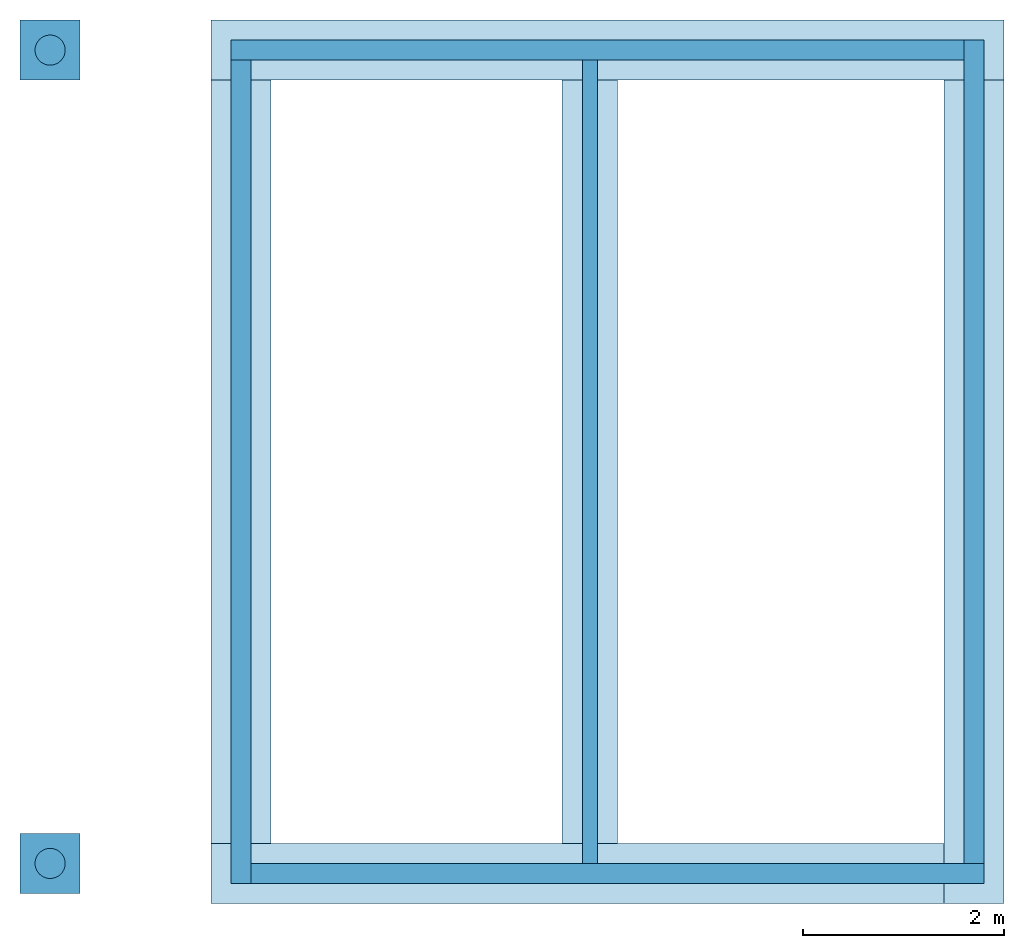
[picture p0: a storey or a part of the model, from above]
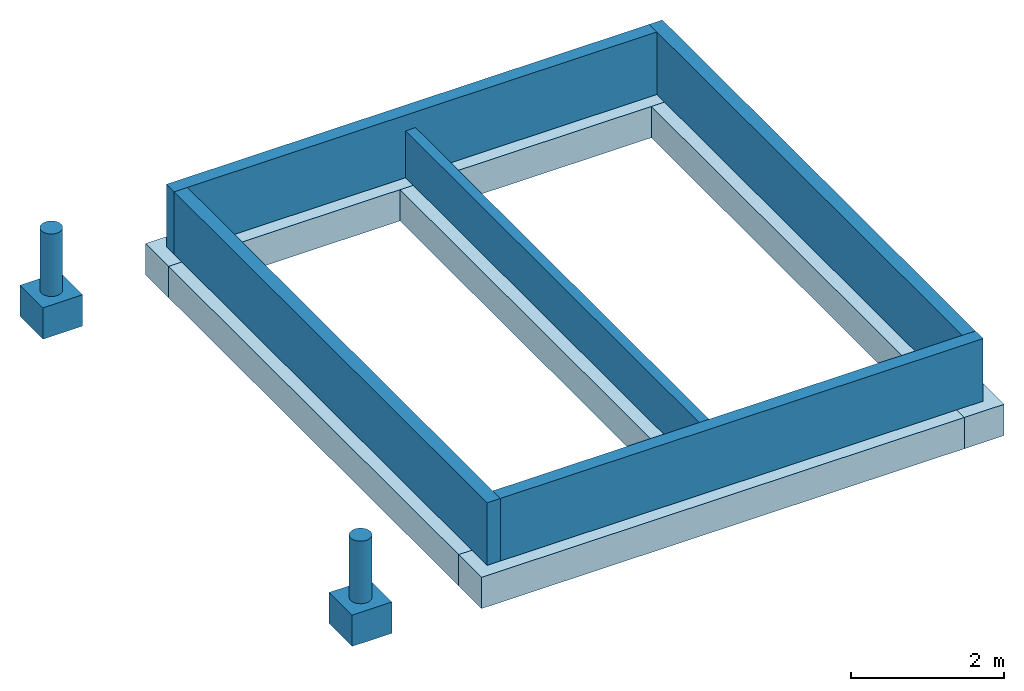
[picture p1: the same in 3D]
Properties of the parts of a building model (IFC2X3)

# File
Description: ViewDefinition [CoordinationView, QuantityTakeOffAddOnView]
File name: Numéro du projet
Time: 2016-11-08T15:51:28
Written by: The EXPRESS Data Manager Version 5.02.0100.07 : 28 Aug 2013
Made in: 20150220_1215(x64) - Exporter 16.0.428.0 - Default UI
Comment: STEP Physical File produced by: The EXPRESS Data Manager Version 5.02.0100.07 : 28 Aug 2013 * Module: EDMstepFileFactory/EDMstandAlone * Creation date: Tue Nov 08 15:51:28 2016 * Host: FC214POSTEPROF * Database: C:\Users\poutead\AppData\Local\Temp\{FD1324F0-440A-46DE-A54C-80044E7AAA6C}\ifc * Database version: 5507 * Database creation date: Tue Nov 08 15:51:26 2016 * Schema: IFC2X3 * Model: DataRepository.ifc * Model creation date: Tue Nov 08 15:51:26 2016 * Header model: DataRepository.ifc_HeaderModel * Header model creation date: Tue Nov 08 15:51:26 2016 * EDMuser: sdai-user * EDMgroup: sdai-group * License ID and type: 5605 : Permanent license. Expiry date: * EDMstepFileFactory options: 020000

# IfcProject, Numéro du projet
LongName: Nom du projet; Phase: Etat du projet

# IfcSite, Default
RefLatitude: 48, 51, 23, 999633; RefLongitude: 2, 21, 3, 553905; RefElevation: 0 m
Autre - Adresse du projet: Entrer l'adresse ici; Catégorie: Informations sur le projet; Date de fin du projet: Date de fin; Etat du projet: Etat du projet; Nom du client: Propriétaire; Nom du projet: Nom du projet; Numéro de projet: Numéro du projet

# IfcBuilding
Pset_BuildingCommon - NumberOfStoreys: 4
Autre - Catégorie: Informations sur le projet; Adresse du projet: Entrer l'adresse ici; Date de fin du projet: Date de fin; Etat du projet: Etat du projet; Nom du client: Propriétaire; Nom du projet: Nom du projet; Numéro de projet: Numéro du projet

# IfcBuildingStorey (4)
Autre - Catégorie: Niveaux; Famille: Niveau: Ligne du Niveau; Famille et type: Niveau: Ligne du Niveau; ID du type: Niveau: Ligne du Niveau; Type: Niveau: Ligne du Niveau; Nom de la famille: Niveau
Cotes - Hauteur de calcul: 0 m
Données d'identification - Structure: no; Etage de bâtiment: yes; Nom du type: Ligne du Niveau
Contraintes - Base de l'élévation: Point de base du projet
Graphismes - Couleur: 12632256; Epaisseur des lignes: 1; Motif des lignes: Tiret point; Symbole: Marqueur de niveau - Point triangulaire: Marqueur de niveau - Point triangulaire; Valeur par défaut du symbole à l'extrémité 1: no; Valeur par défaut du symbole à l'extrémité 2: yes
Name | LongName = Nom | Elevation (m) | Elévation (m)
0_Fondations | 0_Fondations | -1 | -1
Niveau 0 | Niveau 0 | -1.94916e-14 | 0
Niveau 1 | Niveau 1 | 3 | 3
Niveau 2 | Niveau 2 | 6 | 6

# IfcBeam: Poutre rectangulaire - Béton:300 x 600 mm:240493 (3)
In: Niveau 1
Material: Béton - Béton coulé sur place
Pset_BeamCommon - IsExternal: no; LoadBearing: yes; Slope: 0 deg; Reference: 300 x 600 mm
Autre - Catégorie: Ossature; Famille: Poutre rectangulaire - Béton: 300 x 600 mm; Famille et type: Poutre rectangulaire - Béton: 300 x 600 mm; ID du type: Poutre rectangulaire - Béton: 300 x 600 mm; Type: Poutre rectangulaire - Béton: 300 x 600 mm; Nom de la famille: Poutre rectangulaire - Béton
Contraintes - Décalage du niveau d'arrivée: 0 m; Décalage du niveau de départ: 0 m; Elévation du niveau de référence: 3 m; Niveau de référence: Niveau: Niveau 1; Orientation: Normale; Plan de construction: Niveau : Niveau 1; Rotation de la section: 0 deg
Cotes - Elévation à la base: 2.6 m; Elévation en haut: 3 m; b: 0.3 m; h: 0.4 m
Matériaux et finitions - Matériau structurel: Béton - Béton coulé sur place
Phase de construction - Phase de création: Nouvelle construction
Position géométrique - Etat de la jonction: Deux jonctions activées; Justification Y: Origine; Justification YZ: Uniforme; Justification Z: Haut; Valeur de décalage Y: 0 m; Valeur de décalage Z: 0 m
Structure - Enrobage d'armature - Autres faces: Paramètres de l'enrobage d'armature: Enrobage d'armature 1; Enrobage d'armature - Face inférieure: Paramètres de l'enrobage d'armature: Enrobage d'armature 1; Enrobage d'armature - Face supérieure: Paramètres de l'enrobage d'armature: Enrobage d'armature 1; Activer le modèle analytique: yes; Forme de coupe: 0
Données d'identification - Nom du type: 300 x 600 mm
Name (Poutre rectangulaire - Béton:300 x 600 mm:...) | GrossVolume (m3) | Span (m) = Longueur (m) | Surface (m2) | Volume (m3) | Longueur de coupe (m) | Utilisation structurelle
240555 | 0.788465 | 1.94 | 1.56189 | 0.240324 | 2.1027 | Autre
240597 | 0.764843 | 1.94 | 1.54389 | 0.233124 | 2.1027 | Autre
240628 | 3.18898 | 8.1 | 5.79 | 0.972 | 8.1 | Longeron | Structure - Type d'attachement de début: Elévation d'arrivée; Type d'attachement de fin: Elévation d'arrivée

# IfcColumn: 300mm (4)
Type - ElementType: 300mm; PredefinedType: COLUMN; Material: Maçonnerie - Béton coulé sur place
Type - Autre - Catégorie: Poteaux porteurs; Nom de la famille: Poteau béton - Arrondi
Type - Cotes - b: 0.3 m
Type - Données d'identification - Nom du type: 300mm
Type - Structure - Forme de coupe: 0
BaseQuantities - CrossSectionArea: 0.070592 m2; GrossVolume: 0.834857 m3
Pset_ColumnCommon - IsExternal: no; LoadBearing: yes; Reference: 300mm; Slope: 0 deg
Autre - Famille: Poteau béton - Arrondi: 300mm; Famille et type: Poteau béton - Arrondi: 300mm; ID du type: Poteau béton - Arrondi: 300mm; Type: Poteau béton - Arrondi: 300mm
Contraintes - Décalage inférieur: 0 m; Limite de pièce: yes; Décalage supérieur: -0.4 m; Niveau: Niveau: 0_Fondations; Niveau de base: Niveau: 0_Fondations; Niveau supérieur: Niveau: Niveau 1; Se déplace avec les quadrillages: yes; Style de poteau: Vertical
Cotes - Longueur: 3.6 m; Surface: 1.76713 m2; Volume: 0.254464 m3
Matériaux et finitions - Matériau structurel: Maçonnerie - Béton coulé sur place
Phase de construction - Phase de création: Nouvelle construction
Structure - Enrobage d'armature - Autres faces: Paramètres de l'enrobage d'armature: Enrobage d'armature 1; Enrobage d'armature - Face inférieure: Paramètres de l'enrobage d'armature: Enrobage d'armature 1; Enrobage d'armature - Face supérieure: Paramètres de l'enrobage d'armature: Enrobage d'armature 1; Activer le modèle analytique: yes
Name (Poteau béton - Arrondi:300mm:...) | In | Length (m) | OuterSurfaceArea (m2)
237500 | 0_Fondations | 1 | 1.08337
237500 | Niveau 0 | 2.6 | 2.59087
237724 | 0_Fondations | 1 | 1.08337
237724 | Niveau 0 | 2.6 | 2.59087

# IfcDoor: Lisse - 0.90 m x 2.15 m, Ext. Simple:Lisse - 0.90 m x 2.15 m:259105
In: Niveau 0
Type - OperationType: SINGLE_SWING_RIGHT; ParameterTakesPrecedence: no; Sizeable: no; Material: PVC - Blanc
Type - Ext. Simple:Lisse - 0.90 m x 2.15 m:259105 - PanelOperation: SWINGING
Type - Autre - Catégorie: Portes; Nom de la famille: Ext. Simple
Type - Construction - Fonction: Extérieur; Fermeture du mur: Par hôte
Type - Cotes - Epaisseur: 0.05 m; Epaisseur d'isolation: 0.1 m; Hauteur: 2.15 m; Largeur: 0.9 m
Type - Données d'identification - Marque de type: 28; Nom du type: Lisse - 0.90 m x 2.15 m
Type - Graphismes - Type de panneau: Panneau plein
Type - Matériaux et finitions - Cadre: PVC - Blanc; Panneau: PVC - Blanc; Poignée: PVC - Blanc
Type - Propriétés analytiques - Coefficient d'apport thermique solaire: 0.86; Coefficient de transfert de chaleur (U): 5.5617; Construction analytique: Grandes fenêtres à vitrage simple; Résistance thermique (R): 0.179801; Transmission de la lumière visible: 0.9
OverallHeight: 2.2 m; OverallWidth: 1 m
Pset_DoorCommon - IsExternal: yes; Reference: Lisse - 0.90 m x 2.15 m; ThermalTransmittance: 5.5617 kg/K/s3
BaseQuantities - Height: 2.15 m; Width: 0.9 m; Area: 1.935 m2
Autre - ID hôte: Mur de base: Ext. Parpaing 20 + Isolant 10; Famille: Ext. Simple: Lisse - 0.90 m x 2.15 m; Famille et type: Ext. Simple: Lisse - 0.90 m x 2.15 m; Hauteur sous linteau: 2.15 m; ID du type: Ext. Simple: Lisse - 0.90 m x 2.15 m; Type: Ext. Simple: Lisse - 0.90 m x 2.15 m
Contraintes - Niveau: Niveau: Niveau 0; Hauteur de l'appui: 0 m
Cotes - Surface: 2.96758 m2; Volume: 0.0950052 m3
Données d'identification - Identifiant: 1
Graphismes - Angle d'ouverture 2D fixe: yes; Angle d'ouverture 3D: 20 deg
Phase de construction - Phase de création: Nouvelle construction

# IfcFooting: Semelle filante:Soubassement 30 cm/30 cm x 50 cm (5)
In: 0_Fondations
PredefinedType: STRIP_FOOTING; Material: Maçonnerie - Béton
Autre - Catégorie: Fondations; Famille: Semelle filante: Soubassement 30 cm/30 cm x 50 cm; Famille et type: Semelle filante: Soubassement 30 cm/30 cm x 50 cm; ID du type: Semelle filante: Soubassement 30 cm/30 cm x 50 cm; Type: Semelle filante: Soubassement 30 cm/30 cm x 50 cm; Nom de la famille: Semelle filante
Cotes - Elévation à la base: -1.5 m; Elévation en haut: -1 m; Epaisseur de fondation: 0.5 m; Largeur côté extérieur: 0.2 m; Largeur côté intérieur: 0.2 m; Longueur de l'extension de fin par défaut: 0 m; Ne pas couper aux insertions: no
Phase de construction - Phase de création: Nouvelle construction
Structure - Activer le modèle analytique: no; Enrobage d'armature - Autres faces: Paramètres de l'enrobage d'armature: Enrobage d'armature 1; Enrobage d'armature - Face inférieure: Paramètres de l'enrobage d'armature: Enrobage d'armature 1; Enrobage d'armature - Face supérieure: Paramètres de l'enrobage d'armature: Enrobage d'armature 1; Utilisation structurelle: Soutènement
Données d'identification - Nom du type: Soubassement 30 cm/30 cm x 50 cm
Matériaux et finitions - Matériau structurel: Maçonnerie - Béton
Name (Semelle filante:Soubassement 30 cm/30 cm x 50 cm:...) | Largeur (m) | Longueur (m) | Surface (m2) | Volume (m3)
236222 | 0.6 | 7.3 | 4.74 | 2.37
236231 | 0.6 | 8.2 | 4.92 | 2.46
236240 | 0.6 | 7.3 | 4.38 | 2.19
236249 | 0.6 | 8.2 | 4.56 | 2.28
236468 | 0.55 | 8 | 4.18 | 2.09

# IfcRoof: Toit de base:Toit - 200 mm, Toit de base:Toit - 200 mm:243233
In: Niveau 2
Pset_RoofCommon - IsExternal: yes; Reference: Toit - 200 mm; TotalArea: 48.1812 m2; ProjectedArea: 41.7262 m2
Autre - Catégorie: Toits; Famille: Toit de base: Toit - 200 mm; Famille et type: Toit de base: Toit - 200 mm; ID du type: Toit de base: Toit - 200 mm; Type: Toit de base: Toit - 200 mm; Nom de la famille: Toit de base
Construction - Chevron ou ferme: Ferme; Coupe en chevron: Coupe verticale; Hauteur maximale de l'arrête: 7.39018 m; Profondeur du bord de toiture: 0 m; Epaisseur par défaut: 0.2 m
Contraintes - Lié au volume: no; Limite de pièce: yes; Décalage de la coupure: 0 m; Décalage inférieur à partir du niveau: 0 m; Niveau de base: Niveau: Niveau 2
Cotes - Epaisseur: 0.2 m; Inclinaison: 0.57735; Surface: 48.1812 m2; Volume: 9.63624 m3
Phase de construction - Phase de création: Nouvelle construction
Données d'identification - Nom du type: Toit - 200 mm
Graphismes - Couleur vue détail faible: 0
Propriétés analytiques - Rugosité: 3; Coefficient d'absorbance: 0.7

# IfcSlab: Base rectangulaire:1800mm x 1200mm x 450mm (2)
In: 0_Fondations
PredefinedType: FLOOR; Material: Béton - Béton coulé sur place
Pset_SlabCommon - IsExternal: no; LoadBearing: yes; Reference: 1800mm x 1200mm x 450mm
Autre - Catégorie: Fondations; Famille: Base rectangulaire: 1800mm x 1200mm x 450mm; Famille et type: Base rectangulaire: 1800mm x 1200mm x 450mm; ID du type: Base rectangulaire: 1800mm x 1200mm x 450mm; Type: Base rectangulaire: 1800mm x 1200mm x 450mm; Nom de la famille: Base rectangulaire
Contraintes - Se déplace avec les quadrillages: yes; Décalage: 0 m; Hôte: Niveau : 0_Fondations; Niveau: Niveau: 0_Fondations
Cotes - Elévation à la base: -1.5 m; Elévation en haut: -1 m; Largeur: 0.6 m; Longueur: 0.6 m; Surface: 0.72 m2; Volume: 0.36 m3; Epaisseur: 0.5 m
Matériaux et finitions - Matériau structurel: Béton - Béton coulé sur place
Phase de construction - Phase de création: Nouvelle construction
Structure - Enrobage d'armature - Autres faces: Paramètres de l'enrobage d'armature: Enrobage d'armature 1; Enrobage d'armature - Face inférieure: Paramètres de l'enrobage d'armature: Enrobage d'armature 1; Enrobage d'armature - Face supérieure: Paramètres de l'enrobage d'armature: Enrobage d'armature 1; Activer le modèle analytique: yes
Données d'identification - Nom du type: 1800mm x 1200mm x 450mm
Name (Base rectangulaire:1800mm x 1200mm x 450mm:...)
238527
238652

# IfcSlab: Sol:Dalle en béton - 250 mm, Sol:Dalle en béton - 250 mm:236474
In: Niveau 0
PredefinedType: FLOOR; Material: Maçonnerie - Béton 0.25 m
Pset_SlabCommon - Reference: Dalle en béton - 250 mm; IsExternal: no; LoadBearing: yes; PitchAngle: 0 deg
BaseQuantities - GrossArea: 56.8 m2; GrossVolume: 14.2 m3; Perimeter: 30.2 m; Width: 0.25 m
Autre - Catégorie: Sols; Famille: Sol: Dalle en béton - 250 mm; Famille et type: Sol: Dalle en béton - 250 mm; ID du type: Sol: Dalle en béton - 250 mm; Type: Sol: Dalle en béton - 250 mm; Nom de la famille: Sol
Contraintes - Lié au volume: no; Limite de pièce: yes; Décalage par rapport au niveau: 0 m; Niveau: Niveau: Niveau 0
Cotes - Elévation à la base: -0.25 m; Elévation au niveau du noyau inférieur: -0.25 m; Elévation au niveau du noyau supérieur: 0 m; Elévation en haut: 0 m; Epaisseur: 0.25 m; Périmètre: 30.2 m; Surface: 56.8 m2; Volume: 14.2 m3
Phase de construction - Phase de création: Nouvelle construction
Structure - Enrobage d'armature - Autres faces: Paramètres de l'enrobage d'armature: Enrobage d'armature 1; Enrobage d'armature - Face inférieure: Paramètres de l'enrobage d'armature: Enrobage d'armature 1; Enrobage d'armature - Face supérieure: Paramètres de l'enrobage d'armature: Enrobage d'armature 1; Activer le modèle analytique: yes; Structure: yes
Construction - Epaisseur par défaut: 0.25 m; Fonction: Intérieur
Données d'identification - Nom du type: Dalle en béton - 250 mm
Graphismes - Couleur vue détail faible: 0
Matériaux et finitions - Matériau structurel: Maçonnerie - Béton
Propriétés analytiques - Rugosité: 3; Coefficient d'absorbance: 0.7

# IfcSlab: Sol:Dalle en béton - 250 mm 2 (2)
In: Niveau 1
PredefinedType: FLOOR; Material: Maçonnerie - Béton 0.2 m
Pset_SlabCommon - IsExternal: no; LoadBearing: yes; PitchAngle: 0 deg; Reference: Dalle en béton - 250 mm 2
BaseQuantities - Width: 0.2 m
Autre - Catégorie: Sols; Famille: Sol: Dalle en béton - 250 mm 2; Famille et type: Sol: Dalle en béton - 250 mm 2; ID du type: Sol: Dalle en béton - 250 mm 2; Type: Sol: Dalle en béton - 250 mm 2; Nom de la famille: Sol
Contraintes - Lié au volume: no; Limite de pièce: yes; Niveau: Niveau: Niveau 1
Cotes - Epaisseur: 0.2 m
Phase de construction - Phase de création: Nouvelle construction
Structure - Activer le modèle analytique: no; Structure: no
Construction - Fonction: Intérieur; Epaisseur par défaut: 0.2 m
Données d'identification - Nom du type: Dalle en béton - 250 mm 2
Graphismes - Couleur vue détail faible: 0
Matériaux et finitions - Matériau structurel: Maçonnerie - Béton
Propriétés analytiques - Rugosité: 3; Coefficient d'absorbance: 0.7
Name (Sol:Dalle en béton - 250 mm 2:...) | GrossArea (m2) = Surface (m2) | GrossVolume (m3) = Volume (m3) | Perimeter (m) = Périmètre (m) | Décalage par rapport au niveau (m) | Elévation à la base (m) | Elévation en haut (m)
241295 | 12.714 | 2.5428 | 18.86 | -0.1 | 2.7 | 2.9
241453 | 53.1332 | 10.6266 | 30.2 | 0 | 2.8 | 3

# IfcSlab: Toit de base:Toit - 200 mm (4)
In: Niveau 2
PredefinedType: ROOF; Material: Toit par défaut 0.2 m
Pset_SlabCommon - IsExternal: yes; LoadBearing: yes; Reference: Toit - 200 mm; PitchAngle: 30 deg
BaseQuantities - Width: 0.2 m
Name (Toit de base:Toit - 200 mm:...) | GrossArea (m2) | GrossVolume (m3) | Perimeter (m)
2 x 243233 | 0.571372 | 0.114274 | 11.6664
2 x 243233 | 1.66672 | 0.333344 | 20.5149

# IfcStair: Escalier coulé sur place:Monobloc:189391, Escalier coulé sur place:Escalier:261493
In: Niveau 0
Pset_StairCommon - IsExternal: no; Reference: Monobloc; NumberOfRiser: 16; NumberOfTreads: 15; RiserHeight: 0.1875 m; TreadLength: 0.23 m
Autre - Catégorie: Escalier; Famille: Escalier coulé sur place: Monobloc; Famille et type: Escalier coulé sur place: Monobloc; ID du type: Escalier coulé sur place: Monobloc; Type: Escalier coulé sur place: Monobloc; Nom de la famille: Escalier coulé sur place
Contraintes - Décalage inférieur: 0 m; Décalage supérieur: 0 m; Hauteur d'escalier souhaitée: 3 m; Niveau de base: Niveau: Niveau 0; Niveau supérieur: Niveau: Niveau 1
Cotes - Hauteur actuelle de la contremarche: 0.1875 m; Nombre de contremarches souhaité: 16; Nombre réel de contremarches: 16; Numéro initial de marche/contremarche: 1; Profondeur actuelle du giron: 0.23 m
Phase de construction - Phase de création: Nouvelle construction
Structure - Enrobage d'armature: Paramètres de l'enrobage d'armature: Enrobage d'armature 1
Construction - Fonction: Intérieur; Type de palier: Palier monobloc: Epaisseur 150 mm; Type de volée: Volée monobloc: Profondeur de structure 80 mm
Données d'identification - Nom du type: Monobloc
Graphismes - Type de symbole de coupe: Symbole de coupure d'escalier: Zigzag simple
Règles de calcul - Hauteur maximum de la contremarche: 0.19 m; Largeur de volée minimale: 1 m; Profondeur de marche minimale: 0.23 m
Supports - Décalage latéral droit: 0 m; Décalage latéral gauche: 0 m; Nombre de supports intermédiaires: 0; Support droit: Aucun; Support gauche: Aucun; Support intermédiaire: no

# IfcStairFlight: Escalier coulé sur place:Monobloc:189391, Escalier coulé sur place:Escalier:261493 Run 1
In: Niveau 0
NumberOfRiser: 16; NumberOfTreads: 15; RiserHeight: 0.615157 m; TreadLength: 0.754593 m; Material: Maçonnerie - Béton
Pset_StairFlightCommon - Reference: Profondeur de structure 80 mm; NumberOfRiser: 16; NumberOfTreads: 15; RiserHeight: 0.1875 m; TreadLength: 0.23 m; TreadLengthAtOffset: 0.23 m; NosingLength: 0 m; WalkingLineOffset: 0.5 m; WaistThickness: 1 m
Autre - Catégorie: Volées; Famille: Volée monobloc: Profondeur de structure 80 mm; Famille et type: Volée monobloc: Profondeur de structure 80 mm; ID du type: Volée monobloc: Profondeur de structure 80 mm; Type: Volée monobloc: Profondeur de structure 80 mm; Nom de la famille: Volée monobloc
Balancements - Congé d'angle: no; Décalage interne de ligne de foulée: 0.12 m; Largeur minimale à la ligne de foulée: 0.116571 m; Largeur minimale à la limite intérieure: 0.072 m; Marches parallèles à l'arrivée: 2; Marches parallèles au départ: 2; Rayon du congé: 0.18 m; Style de balancement: Equilibré
Construction - Débuter avec contremarche: yes; Etendre la base de contremarche inférieure: 0 m; Finir avec contremarche: yes; Paillasse: Lissée; Profondeur structurelle: 0.08 m
Contraintes - Hauteur de base relative: 0 m; Hauteur de la volée: 3 m; Hauteur maximale relative: 3 m; Ligne de justification: Volée: centre
Cotes - Hauteur réelle des contremarches: 0.1875 m; Largeur réelle de la volée: 1 m; Nombre réel de contremarches: 16; Nombre réel de marches: 15; Profondeur réelle des marches: 0.23 m
Phase de construction - Phase de création: Nouvelle construction
Contremarches - Connexion contremarche à marche: Marche dessous la contremarche; Contremarche: no; Epaisseur de la contremarche: 0 m; Inclinée: no
Données d'identification - Nom du type: Profondeur de structure 80 mm
Marches - Appliquer un nez de marche: Devant seulement; Epaisseur de la marche: 0 m; Longueur du nez de marche: 0 m; Marche: no
Matériaux et finitions - Matériau monobloc: Maçonnerie - Béton

# IfcWall: Mur de base:Ext. Parpaing 20 + Isolant 10 (4)
In: Niveau 0
Type - Autre - Catégorie: Murs; Nom de la famille: Mur de base
Type - Construction - Fonction: Extérieur; Retournement aux extrémités: Aucun(e); Largeur: 0.32 m; Retournement aux insertions: Les deux
Type - Données d'identification - Commentaires du type: Ext. Parpaing 20 + Isolant 10; Nom du type: Ext. Parpaing 20 + Isolant 10
Type - Graphismes - Couleur vue détail faible: 0
Type - Matériaux et finitions - Matériau structurel: Blocs béton manufacturés
Type - Propriétés analytiques - Rugosité: 3; Coefficient d'absorbance: 0.7; Coefficient de transfert de chaleur (U): 6.5; Masse thermique: 302400; Résistance thermique (R): 0.153846
Material: Maçonnerie - Enduit, Blocs béton manufacturés, Maçonnerie - Isolant
Autre - Famille: Mur de base: Ext. Parpaing 20 + Isolant 10; Famille et type: Mur de base: Ext. Parpaing 20 + Isolant 10; ID du type: Mur de base: Ext. Parpaing 20 + Isolant 10; Type: Mur de base: Ext. Parpaing 20 + Isolant 10
Contraintes - Décalage inférieur: 0 m; Décalage supérieur: 0 m; Extension inférieure: 0 m; Extension supérieure: 0 m; Lié au volume: no; Ligne de justification: Nu fini: Extérieur; Limite de pièce: yes; Partie inférieure attachée: no; Partie supérieure attachée: no; Contrainte inférieure: Niveau: Niveau 0; Contrainte supérieure: Niveau: Niveau 1; Hauteur non contrainte: 3 m
Phase de construction - Phase de création: Nouvelle construction
Structure - Activer le modèle analytique: no; Structure: no; Utilisation structurelle: Non porteur
Pset_WallCommon - LoadBearing: no; ExtendToStructure: no; IsExternal: yes; Reference: Ext. Parpaing 20 + Isolant 10; ThermalTransmittance: 6.5 kg/K/s3
Name (Mur de base:Ext. Parpaing 20 + Isolant 10:...) | Longueur (m) | Surface (m2) | Volume (m3)
238881 | 7.22 | 21.0659 | 6.63457
238882 | 8.12 | 22.3728 | 6.98771
238883 | 7.22 | 21.0659 | 6.59706
238884 | 8.12 | 24.36 | 7.68604

# IfcWallStandardCase: Mur de base:Ext. Parpaing 20 + Isolant 10 (4)
In: Niveau 1
Type - Autre - Catégorie: Murs; Nom de la famille: Mur de base
Type - Construction - Fonction: Extérieur; Retournement aux extrémités: Aucun(e); Largeur: 0.32 m; Retournement aux insertions: Les deux
Type - Données d'identification - Commentaires du type: Ext. Parpaing 20 + Isolant 10; Nom du type: Ext. Parpaing 20 + Isolant 10
Type - Graphismes - Couleur vue détail faible: 0
Type - Matériaux et finitions - Matériau structurel: Blocs béton manufacturés
Type - Propriétés analytiques - Rugosité: 3; Coefficient d'absorbance: 0.7; Coefficient de transfert de chaleur (U): 6.5; Masse thermique: 302400; Résistance thermique (R): 0.153846
Material: Maçonnerie - Enduit 0.02 m, Blocs béton manufacturés 0.2 m, Maçonnerie - Isolant 0.1 m
BaseQuantities - Height: 3 m; Width: 0.32 m
Autre - Famille: Mur de base: Ext. Parpaing 20 + Isolant 10; Famille et type: Mur de base: Ext. Parpaing 20 + Isolant 10; ID du type: Mur de base: Ext. Parpaing 20 + Isolant 10; Type: Mur de base: Ext. Parpaing 20 + Isolant 10
Contraintes - Décalage inférieur: 0 m; Décalage supérieur: 0 m; Extension inférieure: 0 m; Extension supérieure: 0 m; Lié au volume: no; Ligne de justification: Nu fini: Extérieur; Limite de pièce: yes; Partie inférieure attachée: no; Partie supérieure attachée: no; Contrainte inférieure: Niveau: Niveau 1; Contrainte supérieure: Niveau: Niveau 2; Hauteur non contrainte: 3 m
Phase de construction - Phase de création: Nouvelle construction
Structure - Activer le modèle analytique: no; Structure: no; Utilisation structurelle: Non porteur
Pset_WallCommon - LoadBearing: no; ExtendToStructure: no; IsExternal: yes; Reference: Ext. Parpaing 20 + Isolant 10; ThermalTransmittance: 6.5 kg/K/s3
Name (Mur de base:Ext. Parpaing 20 + Isolant 10:...) | Length (m) | GrossSideArea (m2) = Surface (m2) | GrossFootprintArea (m2) | GrossVolume (m3) = Volume (m3) | Longueur (m)
241487 | 3.69573 | 10.493 | 1.18263 | 3.35376 | 3.69573
241488 | 8.12 | 23.7659 | 2.5984 | 7.60106 | 8.12
241489 | 3.69573 | 11.0872 | 1.18263 | 3.5479 | 3.69573
241490 | 8.12 | 21.7497 | 2.5984 | 6.94921 | 8.22

# IfcWallStandardCase: Mur de base:Ext. Parpaing 20 + Isolant 11 (3)
In: Niveau 1
Type - PredefinedType: STANDARD; Material: Maçonnerie - Enduit 0.02 m, Blocs béton manufacturés 0.2 m
Type - Autre - Catégorie: Murs; Nom de la famille: Mur de base
Type - Construction - Fonction: Extérieur; Retournement aux extrémités: Aucun(e); Retournement aux insertions: Les deux; Largeur: 0.22 m
Type - Données d'identification - Commentaires du type: Ext. Parpaing 20 + Isolant 10; Nom du type: Ext. Parpaing 20 + Isolant 11
Type - Graphismes - Couleur vue détail faible: 0
Type - Matériaux et finitions - Matériau structurel: Blocs béton manufacturés
Type - Propriétés analytiques - Rugosité: 3; Coefficient de transfert de chaleur (U): 6.5; Coefficient d'absorbance: 0.7; Masse thermique: 302400; Résistance thermique (R): 0.153846
BaseQuantities - Height: 1 m; Width: 0.22 m
Autre - Famille: Mur de base: Ext. Parpaing 20 + Isolant 11; Famille et type: Mur de base: Ext. Parpaing 20 + Isolant 11; ID du type: Mur de base: Ext. Parpaing 20 + Isolant 11; Type: Mur de base: Ext. Parpaing 20 + Isolant 11
Contraintes - Décalage inférieur: 0 m; Extension inférieure: 0 m; Extension supérieure: 0 m; Lié au volume: no; Ligne de justification: Nu fini: Extérieur; Limite de pièce: yes; Partie inférieure attachée: no; Partie supérieure attachée: no; Contrainte supérieure: Niveau: Niveau 1; Contrainte inférieure: Niveau: Niveau 1; Décalage supérieur: 1 m; Hauteur non contrainte: 1 m
Phase de construction - Phase de création: Nouvelle construction
Structure - Activer le modèle analytique: no; Structure: no; Utilisation structurelle: Non porteur
Pset_WallCommon - LoadBearing: no; ExtendToStructure: no; IsExternal: yes; Reference: Ext. Parpaing 20 + Isolant 11; ThermalTransmittance: 6.5 kg/K/s3
Name (Mur de base:Ext. Parpaing 20 + Isolant 11:...) | Length (m) = GrossSideArea (m2) = Surface (m2) | GrossFootprintArea (m2) = GrossVolume (m3) = Volume (m3) | Longueur (m)
242205 | 3.52427 | 0.77534 | 3.57427
242909 | 3.52427 | 0.77534 | 3.57427
243137 | 8 | 1.76 | 8.22

# IfcWallStandardCase: Mur de base:Générique - Ext. 150 mm (2)
Type - PredefinedType: STANDARD; Material: Mur par défaut 0.15 m
Type - Autre - Catégorie: Murs; Nom de la famille: Mur de base
Type - Construction - Fonction: Extérieur; Retournement aux extrémités: Aucun(e); Retournement aux insertions: Ne pas retourner; Largeur: 0.15 m
Type - Données d'identification - Nom du type: Générique - Ext. 150 mm
Type - Graphismes - Couleur vue détail faible: 0
Type - Matériaux et finitions - Matériau structurel: Mur par défaut
Type - Propriétés analytiques - Rugosité: 3; Coefficient d'absorbance: 0.7
BaseQuantities - Width: 0.15 m
Autre - Famille: Mur de base: Générique - Ext. 150 mm; Famille et type: Mur de base: Générique - Ext. 150 mm; ID du type: Mur de base: Générique - Ext. 150 mm; Type: Mur de base: Générique - Ext. 150 mm
Contraintes - Décalage inférieur: 0 m; Décalage supérieur: 0 m; Extension inférieure: 0 m; Extension supérieure: 0 m; Lié au volume: no; Ligne de justification: Nu fini: Extérieur; Limite de pièce: yes; Partie inférieure attachée: no
Phase de construction - Phase de création: Nouvelle construction
Structure - Activer le modèle analytique: no; Structure: no; Utilisation structurelle: Non porteur
Pset_WallCommon - LoadBearing: no; IsExternal: yes; Reference: Générique - Ext. 150 mm
Name (Mur de base:Générique - Ext. 150 mm:...) | In | Height (m) | Length (m) | GrossSideArea (m2) = Surface (m2) | GrossFootprintArea (m2) | GrossVolume (m3) = Volume (m3) | Contrainte inférieure | Contrainte supérieure | Hauteur non contrainte (m) | Partie supérieure attachée = ExtendToStructure | Longueur (m)
236315 | 0_Fondations | 0.75 | 8 | 6 | 1.2 | 0.9 | Niveau: 0_Fondations | Niveau: Niveau 0 | 1 | yes | 8.2
239309 | Niveau 0 | 3 | 7.8 | 23.4 | 1.17 | 3.51 | Niveau: Niveau 0 | Niveau: Niveau 1 | 3 | no | 8.12

# IfcWallStandardCase: Mur de base:Générique - Ext. 200 mm (4)
In: 0_Fondations
Type - PredefinedType: STANDARD; Material: Mur par défaut 0.2 m
Type - Autre - Catégorie: Murs; Nom de la famille: Mur de base
Type - Construction - Fonction: Extérieur; Largeur: 0.2 m; Retournement aux extrémités: Aucun(e); Retournement aux insertions: Ne pas retourner
Type - Données d'identification - Nom du type: Générique - Ext. 200 mm
Type - Graphismes - Couleur vue détail faible: 0
Type - Matériaux et finitions - Matériau structurel: Mur par défaut
Type - Propriétés analytiques - Coefficient d'absorbance: 0.7; Rugosité: 3
BaseQuantities - Height: 1 m; Width: 0.2 m
Autre - Famille: Mur de base: Générique - Ext. 200 mm; Famille et type: Mur de base: Générique - Ext. 200 mm; ID du type: Mur de base: Générique - Ext. 200 mm; Type: Mur de base: Générique - Ext. 200 mm
Contraintes - Contrainte inférieure: Niveau: 0_Fondations; Contrainte supérieure: Niveau: Niveau 0; Décalage inférieur: 0 m; Décalage supérieur: 0 m; Extension inférieure: 0 m; Extension supérieure: 0 m; Hauteur non contrainte: 1 m; Lié au volume: no; Ligne de justification: Nu fini: Extérieur; Limite de pièce: yes; Partie inférieure attachée: no; Partie supérieure attachée: no
Phase de construction - Phase de création: Nouvelle construction
Structure - Activer le modèle analytique: no; Structure: no; Utilisation structurelle: Non porteur
Pset_WallCommon - Reference: Générique - Ext. 200 mm; LoadBearing: no; ExtendToStructure: no; IsExternal: yes
Name (Mur de base:Générique - Ext. 200 mm:...) | Length (m) = GrossSideArea (m2) = Longueur (m) = Surface (m2) | GrossFootprintArea (m2) = GrossVolume (m3) = Volume (m3)
236171 | 7.3 | 1.46
236172 | 8.2 | 1.64
236173 | 7.3 | 1.46
236174 | 8.2 | 1.64

# IfcWindow: 0.60 m x 0.95 m - Appui en aluminium (4)
Type - OperationType: SINGLE_PANEL; ParameterTakesPrecedence: no; Sizeable: no; Material: Fenêtre - Poignée, Fenêtre - Appui, Fenêtre - Vitrage, Fenêtre - Cadre
Type - Autre - Catégorie: Fenêtres; Nom de la famille: 1 Vantail - Droit
Type - Construction - Appui Alu: yes; Fermeture du mur: Extérieur
Type - Contraintes - A: 0 m; A. App.: 96 deg; H. App: 0.015 m
Type - Cotes - Ep. Isolant: 0.1 m; Hauteur: 0.95 m; Hauteur de la poignée: 1.4 m; Largeur: 0.6 m
Type - Données d'identification - Marque de type: 14; Nom du type: 0.60 m x 0.95 m - Appui en aluminium
Type - Matériaux et finitions - Appui: Fenêtre - Appui; Fenêtre: Fenêtre - Cadre; Poignée: Fenêtre - Poignée; Tapées: Fenêtre - Cadre; Vitrage: Fenêtre - Vitrage
Type - Propriétés analytiques - Coefficient d'apport thermique solaire: 0.86; Coefficient de transfert de chaleur (U): 6.7069; Construction analytique: Simple vitrage Pilkington 1/8 po.; Résistance thermique (R): 0.1491; Transmission de la lumière visible: 0.9
OverallHeight: 1.08 m; OverallWidth: 0.7 m
Pset_WindowCommon - IsExternal: yes; Reference: 0.60 m x 0.95 m - Appui en aluminium; ThermalTransmittance: 6.7069 kg/K/s3
BaseQuantities - Height: 0.95 m; Width: 0.6 m; Area: 0.57 m2
Autre - Famille: 1 Vantail - Droit: 0.60 m x 0.95 m - Appui en aluminium; Famille et type: 1 Vantail - Droit: 0.60 m x 0.95 m - Appui en aluminium; ID du type: 1 Vantail - Droit: 0.60 m x 0.95 m - Appui en aluminium; ID hôte: Mur de base: Ext. Parpaing 20 + Isolant 10; Type: 1 Vantail - Droit: 0.60 m x 0.95 m - Appui en aluminium
Cotes - Surface: 1.60015 m2; Volume: 0.0221241 m3
Graphismes - A battant: yes; A soufflet: yes; Encadrement intérieur: no
Phase de construction - Phase de création: Nouvelle construction
Name (1 Vantail - Droit:0.60 m x 0.95 m - Appui en aluminium:...) | In | Hauteur sous linteau (m) | Niveau | Hauteur de l'appui (m) | Identifiant
241536 | Niveau 0 | 1.75 | Niveau: Niveau 0 | 0.8 | 1
241648 | Niveau 0 | 1.75 | Niveau: Niveau 0 | 0.8 | 2
263254 | Niveau 1 | 2 | Niveau: Niveau 1 | 1.05 | 4
263300 | Niveau 1 | 2 | Niveau: Niveau 1 | 1.05 | 5

# IfcWindow: 1.20m x 2.15m, PF 2 Vantaux - Droits:1.20m x 2.15m:246026
In: Niveau 1
Type - OperationType: DOUBLE_PANEL_VERTICAL; ParameterTakesPrecedence: no; Sizeable: no; Material: Fenêtre - Poignée, Fenêtre - Appui, Fenêtre - Cadre, Fenêtre - Vitrage
Type - Autre - Catégorie: Fenêtres; Nom de la famille: PF 2 Vantaux - Droits
Type - Construction - Fermeture du mur: Extérieur
Type - Cotes - Ep. Isolant: 0.1 m; Hauteur: 2.15 m; Hauteur de la poignée: 1.1 m; Largeur: 1.2 m
Type - Données d'identification - Marque de type: 15; Nom du type: 1.20m x 2.15m
Type - Matériaux et finitions - Appui: Fenêtre - Appui; Fenêtre: Fenêtre - Cadre; Poignée: Fenêtre - Poignée; Tapées: Fenêtre - Cadre; Vitrage: Fenêtre - Vitrage
Type - Propriétés analytiques - Construction analytique: <Aucun>
OverallHeight: 2.265 m; OverallWidth: 1.3 m
Pset_WindowCommon - IsExternal: yes; Reference: 1.20m x 2.15m
BaseQuantities - Height: 2.15 m; Width: 1.2 m; Area: 2.58 m2
Autre - ID hôte: Mur de base: Ext. Parpaing 20 + Isolant 10; Famille: PF 2 Vantaux - Droits: 1.20m x 2.15m; Famille et type: PF 2 Vantaux - Droits: 1.20m x 2.15m; Hauteur sous linteau: 2.185 m; ID du type: PF 2 Vantaux - Droits: 1.20m x 2.15m; Type: PF 2 Vantaux - Droits: 1.20m x 2.15m
Contraintes - Hauteur de l'appui: 0.035 m; Niveau: Niveau: Niveau 1
Cotes - Surface: 4.49397 m2; Volume: 0.0688734 m3
Données d'identification - Identifiant: 3
Graphismes - Encadrement intérieur: no
Phase de construction - Phase de création: Nouvelle construction
